VERSION 5.7 ;
BUSBITCHARS "[]" ;
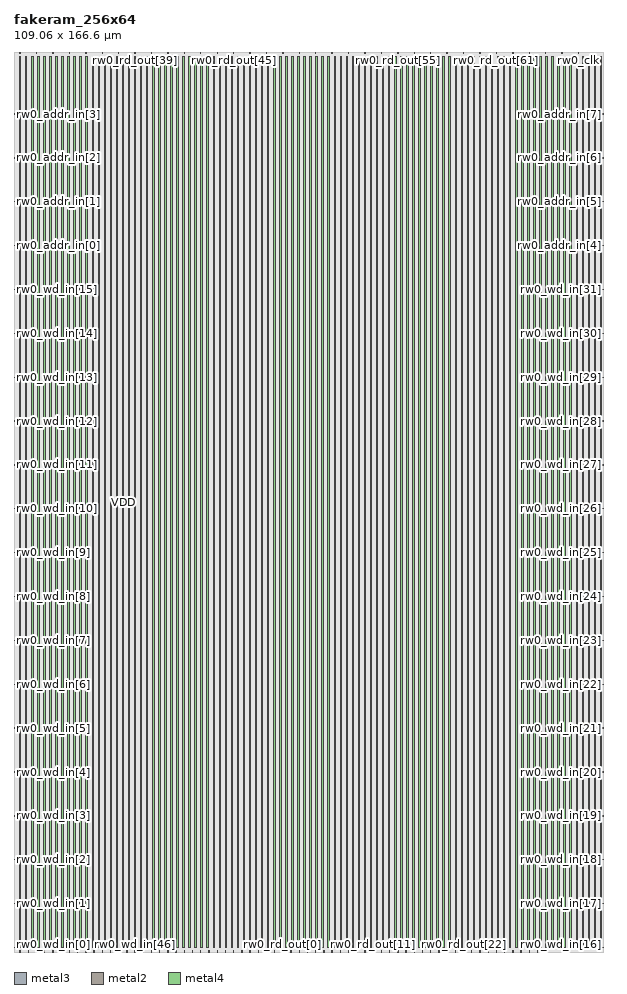
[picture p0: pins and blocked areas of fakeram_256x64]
MACRO fakeram_256x64
  FOREIGN fakeram_256x64 0 0 ;
  SYMMETRY X Y R90 ;
  SIZE 109.060 BY 166.600 ;
  CLASS BLOCK ;
  PIN rw0_wd_in[0]
    DIRECTION INPUT ;
    USE SIGNAL ;
    SHAPE ABUTMENT ;
    PORT
      LAYER metal3 ;
      RECT 0.000 0.805 0.210 0.875 ;
    END
  END rw0_wd_in[0]
  PIN rw0_wd_in[1]
    DIRECTION INPUT ;
    USE SIGNAL ;
    SHAPE ABUTMENT ;
    PORT
      LAYER metal3 ;
      RECT 0.000 8.925 0.210 8.995 ;
    END
  END rw0_wd_in[1]
  PIN rw0_wd_in[2]
    DIRECTION INPUT ;
    USE SIGNAL ;
    SHAPE ABUTMENT ;
    PORT
      LAYER metal3 ;
      RECT 0.000 17.045 0.210 17.115 ;
    END
  END rw0_wd_in[2]
  PIN rw0_wd_in[3]
    DIRECTION INPUT ;
    USE SIGNAL ;
    SHAPE ABUTMENT ;
    PORT
      LAYER metal3 ;
      RECT 0.000 25.165 0.210 25.235 ;
    END
  END rw0_wd_in[3]
  PIN rw0_wd_in[4]
    DIRECTION INPUT ;
    USE SIGNAL ;
    SHAPE ABUTMENT ;
    PORT
      LAYER metal3 ;
      RECT 0.000 33.285 0.210 33.355 ;
    END
  END rw0_wd_in[4]
  PIN rw0_wd_in[5]
    DIRECTION INPUT ;
    USE SIGNAL ;
    SHAPE ABUTMENT ;
    PORT
      LAYER metal3 ;
      RECT 0.000 41.405 0.210 41.475 ;
    END
  END rw0_wd_in[5]
  PIN rw0_wd_in[6]
    DIRECTION INPUT ;
    USE SIGNAL ;
    SHAPE ABUTMENT ;
    PORT
      LAYER metal3 ;
      RECT 0.000 49.525 0.210 49.595 ;
    END
  END rw0_wd_in[6]
  PIN rw0_wd_in[7]
    DIRECTION INPUT ;
    USE SIGNAL ;
    SHAPE ABUTMENT ;
    PORT
      LAYER metal3 ;
      RECT 0.000 57.645 0.210 57.715 ;
    END
  END rw0_wd_in[7]
  PIN rw0_wd_in[8]
    DIRECTION INPUT ;
    USE SIGNAL ;
    SHAPE ABUTMENT ;
    PORT
      LAYER metal3 ;
      RECT 0.000 65.765 0.210 65.835 ;
    END
  END rw0_wd_in[8]
  PIN rw0_wd_in[9]
    DIRECTION INPUT ;
    USE SIGNAL ;
    SHAPE ABUTMENT ;
    PORT
      LAYER metal3 ;
      RECT 0.000 73.885 0.210 73.955 ;
    END
  END rw0_wd_in[9]
  PIN rw0_wd_in[10]
    DIRECTION INPUT ;
    USE SIGNAL ;
    SHAPE ABUTMENT ;
    PORT
      LAYER metal3 ;
      RECT 0.000 82.005 0.210 82.075 ;
    END
  END rw0_wd_in[10]
  PIN rw0_wd_in[11]
    DIRECTION INPUT ;
    USE SIGNAL ;
    SHAPE ABUTMENT ;
    PORT
      LAYER metal3 ;
      RECT 0.000 90.125 0.210 90.195 ;
    END
  END rw0_wd_in[11]
  PIN rw0_wd_in[12]
    DIRECTION INPUT ;
    USE SIGNAL ;
    SHAPE ABUTMENT ;
    PORT
      LAYER metal3 ;
      RECT 0.000 98.245 0.210 98.315 ;
    END
  END rw0_wd_in[12]
  PIN rw0_wd_in[13]
    DIRECTION INPUT ;
    USE SIGNAL ;
    SHAPE ABUTMENT ;
    PORT
      LAYER metal3 ;
      RECT 0.000 106.365 0.210 106.435 ;
    END
  END rw0_wd_in[13]
  PIN rw0_wd_in[14]
    DIRECTION INPUT ;
    USE SIGNAL ;
    SHAPE ABUTMENT ;
    PORT
      LAYER metal3 ;
      RECT 0.000 114.485 0.210 114.555 ;
    END
  END rw0_wd_in[14]
  PIN rw0_wd_in[15]
    DIRECTION INPUT ;
    USE SIGNAL ;
    SHAPE ABUTMENT ;
    PORT
      LAYER metal3 ;
      RECT 0.000 122.605 0.210 122.675 ;
    END
  END rw0_wd_in[15]
  PIN rw0_wd_in[16]
    DIRECTION INPUT ;
    USE SIGNAL ;
    SHAPE ABUTMENT ;
    PORT
      LAYER metal3 ;
      RECT 108.850 0.805 109.060 0.875 ;
    END
  END rw0_wd_in[16]
  PIN rw0_wd_in[17]
    DIRECTION INPUT ;
    USE SIGNAL ;
    SHAPE ABUTMENT ;
    PORT
      LAYER metal3 ;
      RECT 108.850 8.925 109.060 8.995 ;
    END
  END rw0_wd_in[17]
  PIN rw0_wd_in[18]
    DIRECTION INPUT ;
    USE SIGNAL ;
    SHAPE ABUTMENT ;
    PORT
      LAYER metal3 ;
      RECT 108.850 17.045 109.060 17.115 ;
    END
  END rw0_wd_in[18]
  PIN rw0_wd_in[19]
    DIRECTION INPUT ;
    USE SIGNAL ;
    SHAPE ABUTMENT ;
    PORT
      LAYER metal3 ;
      RECT 108.850 25.165 109.060 25.235 ;
    END
  END rw0_wd_in[19]
  PIN rw0_wd_in[20]
    DIRECTION INPUT ;
    USE SIGNAL ;
    SHAPE ABUTMENT ;
    PORT
      LAYER metal3 ;
      RECT 108.850 33.285 109.060 33.355 ;
    END
  END rw0_wd_in[20]
  PIN rw0_wd_in[21]
    DIRECTION INPUT ;
    USE SIGNAL ;
    SHAPE ABUTMENT ;
    PORT
      LAYER metal3 ;
      RECT 108.850 41.405 109.060 41.475 ;
    END
  END rw0_wd_in[21]
  PIN rw0_wd_in[22]
    DIRECTION INPUT ;
    USE SIGNAL ;
    SHAPE ABUTMENT ;
    PORT
      LAYER metal3 ;
      RECT 108.850 49.525 109.060 49.595 ;
    END
  END rw0_wd_in[22]
  PIN rw0_wd_in[23]
    DIRECTION INPUT ;
    USE SIGNAL ;
    SHAPE ABUTMENT ;
    PORT
      LAYER metal3 ;
      RECT 108.850 57.645 109.060 57.715 ;
    END
  END rw0_wd_in[23]
  PIN rw0_wd_in[24]
    DIRECTION INPUT ;
    USE SIGNAL ;
    SHAPE ABUTMENT ;
    PORT
      LAYER metal3 ;
      RECT 108.850 65.765 109.060 65.835 ;
    END
  END rw0_wd_in[24]
  PIN rw0_wd_in[25]
    DIRECTION INPUT ;
    USE SIGNAL ;
    SHAPE ABUTMENT ;
    PORT
      LAYER metal3 ;
      RECT 108.850 73.885 109.060 73.955 ;
    END
  END rw0_wd_in[25]
  PIN rw0_wd_in[26]
    DIRECTION INPUT ;
    USE SIGNAL ;
    SHAPE ABUTMENT ;
    PORT
      LAYER metal3 ;
      RECT 108.850 82.005 109.060 82.075 ;
    END
  END rw0_wd_in[26]
  PIN rw0_wd_in[27]
    DIRECTION INPUT ;
    USE SIGNAL ;
    SHAPE ABUTMENT ;
    PORT
      LAYER metal3 ;
      RECT 108.850 90.125 109.060 90.195 ;
    END
  END rw0_wd_in[27]
  PIN rw0_wd_in[28]
    DIRECTION INPUT ;
    USE SIGNAL ;
    SHAPE ABUTMENT ;
    PORT
      LAYER metal3 ;
      RECT 108.850 98.245 109.060 98.315 ;
    END
  END rw0_wd_in[28]
  PIN rw0_wd_in[29]
    DIRECTION INPUT ;
    USE SIGNAL ;
    SHAPE ABUTMENT ;
    PORT
      LAYER metal3 ;
      RECT 108.850 106.365 109.060 106.435 ;
    END
  END rw0_wd_in[29]
  PIN rw0_wd_in[30]
    DIRECTION INPUT ;
    USE SIGNAL ;
    SHAPE ABUTMENT ;
    PORT
      LAYER metal3 ;
      RECT 108.850 114.485 109.060 114.555 ;
    END
  END rw0_wd_in[30]
  PIN rw0_wd_in[31]
    DIRECTION INPUT ;
    USE SIGNAL ;
    SHAPE ABUTMENT ;
    PORT
      LAYER metal3 ;
      RECT 108.850 122.605 109.060 122.675 ;
    END
  END rw0_wd_in[31]
  PIN rw0_wd_in[32]
    DIRECTION INPUT ;
    USE SIGNAL ;
    SHAPE ABUTMENT ;
    PORT
      LAYER metal2 ;
      RECT 1.105 0.000 1.175 0.210 ;
    END
  END rw0_wd_in[32]
  PIN rw0_wd_in[33]
    DIRECTION INPUT ;
    USE SIGNAL ;
    SHAPE ABUTMENT ;
    PORT
      LAYER metal2 ;
      RECT 2.625 0.000 2.695 0.210 ;
    END
  END rw0_wd_in[33]
  PIN rw0_wd_in[34]
    DIRECTION INPUT ;
    USE SIGNAL ;
    SHAPE ABUTMENT ;
    PORT
      LAYER metal2 ;
      RECT 4.145 0.000 4.215 0.210 ;
    END
  END rw0_wd_in[34]
  PIN rw0_wd_in[35]
    DIRECTION INPUT ;
    USE SIGNAL ;
    SHAPE ABUTMENT ;
    PORT
      LAYER metal2 ;
      RECT 5.665 0.000 5.735 0.210 ;
    END
  END rw0_wd_in[35]
  PIN rw0_wd_in[36]
    DIRECTION INPUT ;
    USE SIGNAL ;
    SHAPE ABUTMENT ;
    PORT
      LAYER metal2 ;
      RECT 7.185 0.000 7.255 0.210 ;
    END
  END rw0_wd_in[36]
  PIN rw0_wd_in[37]
    DIRECTION INPUT ;
    USE SIGNAL ;
    SHAPE ABUTMENT ;
    PORT
      LAYER metal2 ;
      RECT 8.705 0.000 8.775 0.210 ;
    END
  END rw0_wd_in[37]
  PIN rw0_wd_in[38]
    DIRECTION INPUT ;
    USE SIGNAL ;
    SHAPE ABUTMENT ;
    PORT
      LAYER metal2 ;
      RECT 10.225 0.000 10.295 0.210 ;
    END
  END rw0_wd_in[38]
  PIN rw0_wd_in[39]
    DIRECTION INPUT ;
    USE SIGNAL ;
    SHAPE ABUTMENT ;
    PORT
      LAYER metal2 ;
      RECT 11.745 0.000 11.815 0.210 ;
    END
  END rw0_wd_in[39]
  PIN rw0_wd_in[40]
    DIRECTION INPUT ;
    USE SIGNAL ;
    SHAPE ABUTMENT ;
    PORT
      LAYER metal2 ;
      RECT 13.265 0.000 13.335 0.210 ;
    END
  END rw0_wd_in[40]
  PIN rw0_wd_in[41]
    DIRECTION INPUT ;
    USE SIGNAL ;
    SHAPE ABUTMENT ;
    PORT
      LAYER metal2 ;
      RECT 14.785 0.000 14.855 0.210 ;
    END
  END rw0_wd_in[41]
  PIN rw0_wd_in[42]
    DIRECTION INPUT ;
    USE SIGNAL ;
    SHAPE ABUTMENT ;
    PORT
      LAYER metal2 ;
      RECT 16.305 0.000 16.375 0.210 ;
    END
  END rw0_wd_in[42]
  PIN rw0_wd_in[43]
    DIRECTION INPUT ;
    USE SIGNAL ;
    SHAPE ABUTMENT ;
    PORT
      LAYER metal2 ;
      RECT 17.825 0.000 17.895 0.210 ;
    END
  END rw0_wd_in[43]
  PIN rw0_wd_in[44]
    DIRECTION INPUT ;
    USE SIGNAL ;
    SHAPE ABUTMENT ;
    PORT
      LAYER metal2 ;
      RECT 19.345 0.000 19.415 0.210 ;
    END
  END rw0_wd_in[44]
  PIN rw0_wd_in[45]
    DIRECTION INPUT ;
    USE SIGNAL ;
    SHAPE ABUTMENT ;
    PORT
      LAYER metal2 ;
      RECT 20.865 0.000 20.935 0.210 ;
    END
  END rw0_wd_in[45]
  PIN rw0_wd_in[46]
    DIRECTION INPUT ;
    USE SIGNAL ;
    SHAPE ABUTMENT ;
    PORT
      LAYER metal2 ;
      RECT 22.385 0.000 22.455 0.210 ;
    END
  END rw0_wd_in[46]
  PIN rw0_wd_in[47]
    DIRECTION INPUT ;
    USE SIGNAL ;
    SHAPE ABUTMENT ;
    PORT
      LAYER metal2 ;
      RECT 23.905 0.000 23.975 0.210 ;
    END
  END rw0_wd_in[47]
  PIN rw0_wd_in[48]
    DIRECTION INPUT ;
    USE SIGNAL ;
    SHAPE ABUTMENT ;
    PORT
      LAYER metal2 ;
      RECT 25.425 0.000 25.495 0.210 ;
    END
  END rw0_wd_in[48]
  PIN rw0_wd_in[49]
    DIRECTION INPUT ;
    USE SIGNAL ;
    SHAPE ABUTMENT ;
    PORT
      LAYER metal2 ;
      RECT 26.945 0.000 27.015 0.210 ;
    END
  END rw0_wd_in[49]
  PIN rw0_wd_in[50]
    DIRECTION INPUT ;
    USE SIGNAL ;
    SHAPE ABUTMENT ;
    PORT
      LAYER metal2 ;
      RECT 28.465 0.000 28.535 0.210 ;
    END
  END rw0_wd_in[50]
  PIN rw0_wd_in[51]
    DIRECTION INPUT ;
    USE SIGNAL ;
    SHAPE ABUTMENT ;
    PORT
      LAYER metal2 ;
      RECT 29.985 0.000 30.055 0.210 ;
    END
  END rw0_wd_in[51]
  PIN rw0_wd_in[52]
    DIRECTION INPUT ;
    USE SIGNAL ;
    SHAPE ABUTMENT ;
    PORT
      LAYER metal2 ;
      RECT 31.505 0.000 31.575 0.210 ;
    END
  END rw0_wd_in[52]
  PIN rw0_wd_in[53]
    DIRECTION INPUT ;
    USE SIGNAL ;
    SHAPE ABUTMENT ;
    PORT
      LAYER metal2 ;
      RECT 33.025 0.000 33.095 0.210 ;
    END
  END rw0_wd_in[53]
  PIN rw0_wd_in[54]
    DIRECTION INPUT ;
    USE SIGNAL ;
    SHAPE ABUTMENT ;
    PORT
      LAYER metal2 ;
      RECT 34.545 0.000 34.615 0.210 ;
    END
  END rw0_wd_in[54]
  PIN rw0_wd_in[55]
    DIRECTION INPUT ;
    USE SIGNAL ;
    SHAPE ABUTMENT ;
    PORT
      LAYER metal2 ;
      RECT 36.065 0.000 36.135 0.210 ;
    END
  END rw0_wd_in[55]
  PIN rw0_wd_in[56]
    DIRECTION INPUT ;
    USE SIGNAL ;
    SHAPE ABUTMENT ;
    PORT
      LAYER metal2 ;
      RECT 37.585 0.000 37.655 0.210 ;
    END
  END rw0_wd_in[56]
  PIN rw0_wd_in[57]
    DIRECTION INPUT ;
    USE SIGNAL ;
    SHAPE ABUTMENT ;
    PORT
      LAYER metal2 ;
      RECT 39.105 0.000 39.175 0.210 ;
    END
  END rw0_wd_in[57]
  PIN rw0_wd_in[58]
    DIRECTION INPUT ;
    USE SIGNAL ;
    SHAPE ABUTMENT ;
    PORT
      LAYER metal2 ;
      RECT 40.625 0.000 40.695 0.210 ;
    END
  END rw0_wd_in[58]
  PIN rw0_wd_in[59]
    DIRECTION INPUT ;
    USE SIGNAL ;
    SHAPE ABUTMENT ;
    PORT
      LAYER metal2 ;
      RECT 42.145 0.000 42.215 0.210 ;
    END
  END rw0_wd_in[59]
  PIN rw0_wd_in[60]
    DIRECTION INPUT ;
    USE SIGNAL ;
    SHAPE ABUTMENT ;
    PORT
      LAYER metal2 ;
      RECT 43.665 0.000 43.735 0.210 ;
    END
  END rw0_wd_in[60]
  PIN rw0_wd_in[61]
    DIRECTION INPUT ;
    USE SIGNAL ;
    SHAPE ABUTMENT ;
    PORT
      LAYER metal2 ;
      RECT 45.185 0.000 45.255 0.210 ;
    END
  END rw0_wd_in[61]
  PIN rw0_wd_in[62]
    DIRECTION INPUT ;
    USE SIGNAL ;
    SHAPE ABUTMENT ;
    PORT
      LAYER metal2 ;
      RECT 46.705 0.000 46.775 0.210 ;
    END
  END rw0_wd_in[62]
  PIN rw0_wd_in[63]
    DIRECTION INPUT ;
    USE SIGNAL ;
    SHAPE ABUTMENT ;
    PORT
      LAYER metal2 ;
      RECT 48.225 0.000 48.295 0.210 ;
    END
  END rw0_wd_in[63]
  PIN rw0_rd_out[0]
    DIRECTION OUTPUT ;
    USE SIGNAL ;
    SHAPE ABUTMENT ;
    PORT
      LAYER metal2 ;
      RECT 49.745 0.000 49.815 0.210 ;
    END
  END rw0_rd_out[0]
  PIN rw0_rd_out[1]
    DIRECTION OUTPUT ;
    USE SIGNAL ;
    SHAPE ABUTMENT ;
    PORT
      LAYER metal2 ;
      RECT 51.265 0.000 51.335 0.210 ;
    END
  END rw0_rd_out[1]
  PIN rw0_rd_out[2]
    DIRECTION OUTPUT ;
    USE SIGNAL ;
    SHAPE ABUTMENT ;
    PORT
      LAYER metal2 ;
      RECT 52.785 0.000 52.855 0.210 ;
    END
  END rw0_rd_out[2]
  PIN rw0_rd_out[3]
    DIRECTION OUTPUT ;
    USE SIGNAL ;
    SHAPE ABUTMENT ;
    PORT
      LAYER metal2 ;
      RECT 54.305 0.000 54.375 0.210 ;
    END
  END rw0_rd_out[3]
  PIN rw0_rd_out[4]
    DIRECTION OUTPUT ;
    USE SIGNAL ;
    SHAPE ABUTMENT ;
    PORT
      LAYER metal2 ;
      RECT 55.825 0.000 55.895 0.210 ;
    END
  END rw0_rd_out[4]
  PIN rw0_rd_out[5]
    DIRECTION OUTPUT ;
    USE SIGNAL ;
    SHAPE ABUTMENT ;
    PORT
      LAYER metal2 ;
      RECT 57.345 0.000 57.415 0.210 ;
    END
  END rw0_rd_out[5]
  PIN rw0_rd_out[6]
    DIRECTION OUTPUT ;
    USE SIGNAL ;
    SHAPE ABUTMENT ;
    PORT
      LAYER metal2 ;
      RECT 58.865 0.000 58.935 0.210 ;
    END
  END rw0_rd_out[6]
  PIN rw0_rd_out[7]
    DIRECTION OUTPUT ;
    USE SIGNAL ;
    SHAPE ABUTMENT ;
    PORT
      LAYER metal2 ;
      RECT 60.385 0.000 60.455 0.210 ;
    END
  END rw0_rd_out[7]
  PIN rw0_rd_out[8]
    DIRECTION OUTPUT ;
    USE SIGNAL ;
    SHAPE ABUTMENT ;
    PORT
      LAYER metal2 ;
      RECT 61.905 0.000 61.975 0.210 ;
    END
  END rw0_rd_out[8]
  PIN rw0_rd_out[9]
    DIRECTION OUTPUT ;
    USE SIGNAL ;
    SHAPE ABUTMENT ;
    PORT
      LAYER metal2 ;
      RECT 63.425 0.000 63.495 0.210 ;
    END
  END rw0_rd_out[9]
  PIN rw0_rd_out[10]
    DIRECTION OUTPUT ;
    USE SIGNAL ;
    SHAPE ABUTMENT ;
    PORT
      LAYER metal2 ;
      RECT 64.945 0.000 65.015 0.210 ;
    END
  END rw0_rd_out[10]
  PIN rw0_rd_out[11]
    DIRECTION OUTPUT ;
    USE SIGNAL ;
    SHAPE ABUTMENT ;
    PORT
      LAYER metal2 ;
      RECT 66.465 0.000 66.535 0.210 ;
    END
  END rw0_rd_out[11]
  PIN rw0_rd_out[12]
    DIRECTION OUTPUT ;
    USE SIGNAL ;
    SHAPE ABUTMENT ;
    PORT
      LAYER metal2 ;
      RECT 67.985 0.000 68.055 0.210 ;
    END
  END rw0_rd_out[12]
  PIN rw0_rd_out[13]
    DIRECTION OUTPUT ;
    USE SIGNAL ;
    SHAPE ABUTMENT ;
    PORT
      LAYER metal2 ;
      RECT 69.505 0.000 69.575 0.210 ;
    END
  END rw0_rd_out[13]
  PIN rw0_rd_out[14]
    DIRECTION OUTPUT ;
    USE SIGNAL ;
    SHAPE ABUTMENT ;
    PORT
      LAYER metal2 ;
      RECT 71.025 0.000 71.095 0.210 ;
    END
  END rw0_rd_out[14]
  PIN rw0_rd_out[15]
    DIRECTION OUTPUT ;
    USE SIGNAL ;
    SHAPE ABUTMENT ;
    PORT
      LAYER metal2 ;
      RECT 72.545 0.000 72.615 0.210 ;
    END
  END rw0_rd_out[15]
  PIN rw0_rd_out[16]
    DIRECTION OUTPUT ;
    USE SIGNAL ;
    SHAPE ABUTMENT ;
    PORT
      LAYER metal2 ;
      RECT 74.065 0.000 74.135 0.210 ;
    END
  END rw0_rd_out[16]
  PIN rw0_rd_out[17]
    DIRECTION OUTPUT ;
    USE SIGNAL ;
    SHAPE ABUTMENT ;
    PORT
      LAYER metal2 ;
      RECT 75.585 0.000 75.655 0.210 ;
    END
  END rw0_rd_out[17]
  PIN rw0_rd_out[18]
    DIRECTION OUTPUT ;
    USE SIGNAL ;
    SHAPE ABUTMENT ;
    PORT
      LAYER metal2 ;
      RECT 77.105 0.000 77.175 0.210 ;
    END
  END rw0_rd_out[18]
  PIN rw0_rd_out[19]
    DIRECTION OUTPUT ;
    USE SIGNAL ;
    SHAPE ABUTMENT ;
    PORT
      LAYER metal2 ;
      RECT 78.625 0.000 78.695 0.210 ;
    END
  END rw0_rd_out[19]
  PIN rw0_rd_out[20]
    DIRECTION OUTPUT ;
    USE SIGNAL ;
    SHAPE ABUTMENT ;
    PORT
      LAYER metal2 ;
      RECT 80.145 0.000 80.215 0.210 ;
    END
  END rw0_rd_out[20]
  PIN rw0_rd_out[21]
    DIRECTION OUTPUT ;
    USE SIGNAL ;
    SHAPE ABUTMENT ;
    PORT
      LAYER metal2 ;
      RECT 81.665 0.000 81.735 0.210 ;
    END
  END rw0_rd_out[21]
  PIN rw0_rd_out[22]
    DIRECTION OUTPUT ;
    USE SIGNAL ;
    SHAPE ABUTMENT ;
    PORT
      LAYER metal2 ;
      RECT 83.185 0.000 83.255 0.210 ;
    END
  END rw0_rd_out[22]
  PIN rw0_rd_out[23]
    DIRECTION OUTPUT ;
    USE SIGNAL ;
    SHAPE ABUTMENT ;
    PORT
      LAYER metal2 ;
      RECT 84.705 0.000 84.775 0.210 ;
    END
  END rw0_rd_out[23]
  PIN rw0_rd_out[24]
    DIRECTION OUTPUT ;
    USE SIGNAL ;
    SHAPE ABUTMENT ;
    PORT
      LAYER metal2 ;
      RECT 86.225 0.000 86.295 0.210 ;
    END
  END rw0_rd_out[24]
  PIN rw0_rd_out[25]
    DIRECTION OUTPUT ;
    USE SIGNAL ;
    SHAPE ABUTMENT ;
    PORT
      LAYER metal2 ;
      RECT 87.745 0.000 87.815 0.210 ;
    END
  END rw0_rd_out[25]
  PIN rw0_rd_out[26]
    DIRECTION OUTPUT ;
    USE SIGNAL ;
    SHAPE ABUTMENT ;
    PORT
      LAYER metal2 ;
      RECT 89.265 0.000 89.335 0.210 ;
    END
  END rw0_rd_out[26]
  PIN rw0_rd_out[27]
    DIRECTION OUTPUT ;
    USE SIGNAL ;
    SHAPE ABUTMENT ;
    PORT
      LAYER metal2 ;
      RECT 90.785 0.000 90.855 0.210 ;
    END
  END rw0_rd_out[27]
  PIN rw0_rd_out[28]
    DIRECTION OUTPUT ;
    USE SIGNAL ;
    SHAPE ABUTMENT ;
    PORT
      LAYER metal2 ;
      RECT 92.305 0.000 92.375 0.210 ;
    END
  END rw0_rd_out[28]
  PIN rw0_rd_out[29]
    DIRECTION OUTPUT ;
    USE SIGNAL ;
    SHAPE ABUTMENT ;
    PORT
      LAYER metal2 ;
      RECT 93.825 0.000 93.895 0.210 ;
    END
  END rw0_rd_out[29]
  PIN rw0_rd_out[30]
    DIRECTION OUTPUT ;
    USE SIGNAL ;
    SHAPE ABUTMENT ;
    PORT
      LAYER metal2 ;
      RECT 95.345 0.000 95.415 0.210 ;
    END
  END rw0_rd_out[30]
  PIN rw0_rd_out[31]
    DIRECTION OUTPUT ;
    USE SIGNAL ;
    SHAPE ABUTMENT ;
    PORT
      LAYER metal2 ;
      RECT 96.865 0.000 96.935 0.210 ;
    END
  END rw0_rd_out[31]
  PIN rw0_rd_out[32]
    DIRECTION OUTPUT ;
    USE SIGNAL ;
    SHAPE ABUTMENT ;
    PORT
      LAYER metal2 ;
      RECT 1.105 166.390 1.175 166.600 ;
    END
  END rw0_rd_out[32]
  PIN rw0_rd_out[33]
    DIRECTION OUTPUT ;
    USE SIGNAL ;
    SHAPE ABUTMENT ;
    PORT
      LAYER metal2 ;
      RECT 4.145 166.390 4.215 166.600 ;
    END
  END rw0_rd_out[33]
  PIN rw0_rd_out[34]
    DIRECTION OUTPUT ;
    USE SIGNAL ;
    SHAPE ABUTMENT ;
    PORT
      LAYER metal2 ;
      RECT 7.185 166.390 7.255 166.600 ;
    END
  END rw0_rd_out[34]
  PIN rw0_rd_out[35]
    DIRECTION OUTPUT ;
    USE SIGNAL ;
    SHAPE ABUTMENT ;
    PORT
      LAYER metal2 ;
      RECT 10.225 166.390 10.295 166.600 ;
    END
  END rw0_rd_out[35]
  PIN rw0_rd_out[36]
    DIRECTION OUTPUT ;
    USE SIGNAL ;
    SHAPE ABUTMENT ;
    PORT
      LAYER metal2 ;
      RECT 13.265 166.390 13.335 166.600 ;
    END
  END rw0_rd_out[36]
  PIN rw0_rd_out[37]
    DIRECTION OUTPUT ;
    USE SIGNAL ;
    SHAPE ABUTMENT ;
    PORT
      LAYER metal2 ;
      RECT 16.305 166.390 16.375 166.600 ;
    END
  END rw0_rd_out[37]
  PIN rw0_rd_out[38]
    DIRECTION OUTPUT ;
    USE SIGNAL ;
    SHAPE ABUTMENT ;
    PORT
      LAYER metal2 ;
      RECT 19.345 166.390 19.415 166.600 ;
    END
  END rw0_rd_out[38]
  PIN rw0_rd_out[39]
    DIRECTION OUTPUT ;
    USE SIGNAL ;
    SHAPE ABUTMENT ;
    PORT
      LAYER metal2 ;
      RECT 22.385 166.390 22.455 166.600 ;
    END
  END rw0_rd_out[39]
  PIN rw0_rd_out[40]
    DIRECTION OUTPUT ;
    USE SIGNAL ;
    SHAPE ABUTMENT ;
    PORT
      LAYER metal2 ;
      RECT 25.425 166.390 25.495 166.600 ;
    END
  END rw0_rd_out[40]
  PIN rw0_rd_out[41]
    DIRECTION OUTPUT ;
    USE SIGNAL ;
    SHAPE ABUTMENT ;
    PORT
      LAYER metal2 ;
      RECT 28.465 166.390 28.535 166.600 ;
    END
  END rw0_rd_out[41]
  PIN rw0_rd_out[42]
    DIRECTION OUTPUT ;
    USE SIGNAL ;
    SHAPE ABUTMENT ;
    PORT
      LAYER metal2 ;
      RECT 31.505 166.390 31.575 166.600 ;
    END
  END rw0_rd_out[42]
  PIN rw0_rd_out[43]
    DIRECTION OUTPUT ;
    USE SIGNAL ;
    SHAPE ABUTMENT ;
    PORT
      LAYER metal2 ;
      RECT 34.545 166.390 34.615 166.600 ;
    END
  END rw0_rd_out[43]
  PIN rw0_rd_out[44]
    DIRECTION OUTPUT ;
    USE SIGNAL ;
    SHAPE ABUTMENT ;
    PORT
      LAYER metal2 ;
      RECT 37.585 166.390 37.655 166.600 ;
    END
  END rw0_rd_out[44]
  PIN rw0_rd_out[45]
    DIRECTION OUTPUT ;
    USE SIGNAL ;
    SHAPE ABUTMENT ;
    PORT
      LAYER metal2 ;
      RECT 40.625 166.390 40.695 166.600 ;
    END
  END rw0_rd_out[45]
  PIN rw0_rd_out[46]
    DIRECTION OUTPUT ;
    USE SIGNAL ;
    SHAPE ABUTMENT ;
    PORT
      LAYER metal2 ;
      RECT 43.665 166.390 43.735 166.600 ;
    END
  END rw0_rd_out[46]
  PIN rw0_rd_out[47]
    DIRECTION OUTPUT ;
    USE SIGNAL ;
    SHAPE ABUTMENT ;
    PORT
      LAYER metal2 ;
      RECT 46.705 166.390 46.775 166.600 ;
    END
  END rw0_rd_out[47]
  PIN rw0_rd_out[48]
    DIRECTION OUTPUT ;
    USE SIGNAL ;
    SHAPE ABUTMENT ;
    PORT
      LAYER metal2 ;
      RECT 49.745 166.390 49.815 166.600 ;
    END
  END rw0_rd_out[48]
  PIN rw0_rd_out[49]
    DIRECTION OUTPUT ;
    USE SIGNAL ;
    SHAPE ABUTMENT ;
    PORT
      LAYER metal2 ;
      RECT 52.785 166.390 52.855 166.600 ;
    END
  END rw0_rd_out[49]
  PIN rw0_rd_out[50]
    DIRECTION OUTPUT ;
    USE SIGNAL ;
    SHAPE ABUTMENT ;
    PORT
      LAYER metal2 ;
      RECT 55.825 166.390 55.895 166.600 ;
    END
  END rw0_rd_out[50]
  PIN rw0_rd_out[51]
    DIRECTION OUTPUT ;
    USE SIGNAL ;
    SHAPE ABUTMENT ;
    PORT
      LAYER metal2 ;
      RECT 58.865 166.390 58.935 166.600 ;
    END
  END rw0_rd_out[51]
  PIN rw0_rd_out[52]
    DIRECTION OUTPUT ;
    USE SIGNAL ;
    SHAPE ABUTMENT ;
    PORT
      LAYER metal2 ;
      RECT 61.905 166.390 61.975 166.600 ;
    END
  END rw0_rd_out[52]
  PIN rw0_rd_out[53]
    DIRECTION OUTPUT ;
    USE SIGNAL ;
    SHAPE ABUTMENT ;
    PORT
      LAYER metal2 ;
      RECT 64.945 166.390 65.015 166.600 ;
    END
  END rw0_rd_out[53]
  PIN rw0_rd_out[54]
    DIRECTION OUTPUT ;
    USE SIGNAL ;
    SHAPE ABUTMENT ;
    PORT
      LAYER metal2 ;
      RECT 67.985 166.390 68.055 166.600 ;
    END
  END rw0_rd_out[54]
  PIN rw0_rd_out[55]
    DIRECTION OUTPUT ;
    USE SIGNAL ;
    SHAPE ABUTMENT ;
    PORT
      LAYER metal2 ;
      RECT 71.025 166.390 71.095 166.600 ;
    END
  END rw0_rd_out[55]
  PIN rw0_rd_out[56]
    DIRECTION OUTPUT ;
    USE SIGNAL ;
    SHAPE ABUTMENT ;
    PORT
      LAYER metal2 ;
      RECT 74.065 166.390 74.135 166.600 ;
    END
  END rw0_rd_out[56]
  PIN rw0_rd_out[57]
    DIRECTION OUTPUT ;
    USE SIGNAL ;
    SHAPE ABUTMENT ;
    PORT
      LAYER metal2 ;
      RECT 77.105 166.390 77.175 166.600 ;
    END
  END rw0_rd_out[57]
  PIN rw0_rd_out[58]
    DIRECTION OUTPUT ;
    USE SIGNAL ;
    SHAPE ABUTMENT ;
    PORT
      LAYER metal2 ;
      RECT 80.145 166.390 80.215 166.600 ;
    END
  END rw0_rd_out[58]
  PIN rw0_rd_out[59]
    DIRECTION OUTPUT ;
    USE SIGNAL ;
    SHAPE ABUTMENT ;
    PORT
      LAYER metal2 ;
      RECT 83.185 166.390 83.255 166.600 ;
    END
  END rw0_rd_out[59]
  PIN rw0_rd_out[60]
    DIRECTION OUTPUT ;
    USE SIGNAL ;
    SHAPE ABUTMENT ;
    PORT
      LAYER metal2 ;
      RECT 86.225 166.390 86.295 166.600 ;
    END
  END rw0_rd_out[60]
  PIN rw0_rd_out[61]
    DIRECTION OUTPUT ;
    USE SIGNAL ;
    SHAPE ABUTMENT ;
    PORT
      LAYER metal2 ;
      RECT 89.265 166.390 89.335 166.600 ;
    END
  END rw0_rd_out[61]
  PIN rw0_rd_out[62]
    DIRECTION OUTPUT ;
    USE SIGNAL ;
    SHAPE ABUTMENT ;
    PORT
      LAYER metal2 ;
      RECT 92.305 166.390 92.375 166.600 ;
    END
  END rw0_rd_out[62]
  PIN rw0_rd_out[63]
    DIRECTION OUTPUT ;
    USE SIGNAL ;
    SHAPE ABUTMENT ;
    PORT
      LAYER metal2 ;
      RECT 95.345 166.390 95.415 166.600 ;
    END
  END rw0_rd_out[63]
  PIN rw0_addr_in[0]
    DIRECTION INPUT ;
    USE SIGNAL ;
    SHAPE ABUTMENT ;
    PORT
      LAYER metal3 ;
      RECT 0.000 130.725 0.210 130.795 ;
    END
  END rw0_addr_in[0]
  PIN rw0_addr_in[1]
    DIRECTION INPUT ;
    USE SIGNAL ;
    SHAPE ABUTMENT ;
    PORT
      LAYER metal3 ;
      RECT 0.000 138.845 0.210 138.915 ;
    END
  END rw0_addr_in[1]
  PIN rw0_addr_in[2]
    DIRECTION INPUT ;
    USE SIGNAL ;
    SHAPE ABUTMENT ;
    PORT
      LAYER metal3 ;
      RECT 0.000 146.965 0.210 147.035 ;
    END
  END rw0_addr_in[2]
  PIN rw0_addr_in[3]
    DIRECTION INPUT ;
    USE SIGNAL ;
    SHAPE ABUTMENT ;
    PORT
      LAYER metal3 ;
      RECT 0.000 155.085 0.210 155.155 ;
    END
  END rw0_addr_in[3]
  PIN rw0_addr_in[4]
    DIRECTION INPUT ;
    USE SIGNAL ;
    SHAPE ABUTMENT ;
    PORT
      LAYER metal3 ;
      RECT 108.850 130.725 109.060 130.795 ;
    END
  END rw0_addr_in[4]
  PIN rw0_addr_in[5]
    DIRECTION INPUT ;
    USE SIGNAL ;
    SHAPE ABUTMENT ;
    PORT
      LAYER metal3 ;
      RECT 108.850 138.845 109.060 138.915 ;
    END
  END rw0_addr_in[5]
  PIN rw0_addr_in[6]
    DIRECTION INPUT ;
    USE SIGNAL ;
    SHAPE ABUTMENT ;
    PORT
      LAYER metal3 ;
      RECT 108.850 146.965 109.060 147.035 ;
    END
  END rw0_addr_in[6]
  PIN rw0_addr_in[7]
    DIRECTION INPUT ;
    USE SIGNAL ;
    SHAPE ABUTMENT ;
    PORT
      LAYER metal3 ;
      RECT 108.850 155.085 109.060 155.155 ;
    END
  END rw0_addr_in[7]
  PIN rw0_we_in
    DIRECTION INPUT ;
    USE SIGNAL ;
    SHAPE ABUTMENT ;
    PORT
      LAYER metal2 ;
      RECT 98.385 166.390 98.455 166.600 ;
    END
  END rw0_we_in
  PIN rw0_ce_in
    DIRECTION INPUT ;
    USE SIGNAL ;
    SHAPE ABUTMENT ;
    PORT
      LAYER metal2 ;
      RECT 101.425 166.390 101.495 166.600 ;
    END
  END rw0_ce_in
  PIN rw0_clk
    DIRECTION INPUT ;
    USE SIGNAL ;
    SHAPE ABUTMENT ;
    PORT
      LAYER metal2 ;
      RECT 104.465 166.390 104.535 166.600 ;
    END
  END rw0_clk
  PIN VSS
    DIRECTION INOUT ;
    USE GROUND ;
    PORT
      LAYER metal4 ;
      RECT 1.000 0.840 1.280 165.760 ;
      RECT 3.240 0.840 3.520 165.760 ;
      RECT 5.480 0.840 5.760 165.760 ;
      RECT 7.720 0.840 8.000 165.760 ;
      RECT 9.960 0.840 10.240 165.760 ;
      RECT 12.200 0.840 12.480 165.760 ;
      RECT 14.440 0.840 14.720 165.760 ;
      RECT 16.680 0.840 16.960 165.760 ;
      RECT 18.920 0.840 19.200 165.760 ;
      RECT 21.160 0.840 21.440 165.760 ;
      RECT 23.400 0.840 23.680 165.760 ;
      RECT 25.640 0.840 25.920 165.760 ;
      RECT 27.880 0.840 28.160 165.760 ;
      RECT 30.120 0.840 30.400 165.760 ;
      RECT 32.360 0.840 32.640 165.760 ;
      RECT 34.600 0.840 34.880 165.760 ;
      RECT 36.840 0.840 37.120 165.760 ;
      RECT 39.080 0.840 39.360 165.760 ;
      RECT 41.320 0.840 41.600 165.760 ;
      RECT 43.560 0.840 43.840 165.760 ;
      RECT 45.800 0.840 46.080 165.760 ;
      RECT 48.040 0.840 48.320 165.760 ;
      RECT 50.280 0.840 50.560 165.760 ;
      RECT 52.520 0.840 52.800 165.760 ;
      RECT 54.760 0.840 55.040 165.760 ;
      RECT 57.000 0.840 57.280 165.760 ;
      RECT 59.240 0.840 59.520 165.760 ;
      RECT 61.480 0.840 61.760 165.760 ;
      RECT 63.720 0.840 64.000 165.760 ;
      RECT 65.960 0.840 66.240 165.760 ;
      RECT 68.200 0.840 68.480 165.760 ;
      RECT 70.440 0.840 70.720 165.760 ;
      RECT 72.680 0.840 72.960 165.760 ;
      RECT 74.920 0.840 75.200 165.760 ;
      RECT 77.160 0.840 77.440 165.760 ;
      RECT 79.400 0.840 79.680 165.760 ;
      RECT 81.640 0.840 81.920 165.760 ;
      RECT 83.880 0.840 84.160 165.760 ;
      RECT 86.120 0.840 86.400 165.760 ;
      RECT 88.360 0.840 88.640 165.760 ;
      RECT 90.600 0.840 90.880 165.760 ;
      RECT 92.840 0.840 93.120 165.760 ;
      RECT 95.080 0.840 95.360 165.760 ;
      RECT 97.320 0.840 97.600 165.760 ;
      RECT 99.560 0.840 99.840 165.760 ;
      RECT 101.800 0.840 102.080 165.760 ;
      RECT 104.040 0.840 104.320 165.760 ;
      RECT 106.280 0.840 106.560 165.760 ;
      RECT 108.520 0.840 108.800 165.760 ;
    END
  END VSS
  PIN VDD
    DIRECTION INOUT ;
    USE POWER ;
    PORT
      LAYER metal4 ;
      RECT 2.120 0.840 2.400 165.760 ;
      RECT 4.360 0.840 4.640 165.760 ;
      RECT 6.600 0.840 6.880 165.760 ;
      RECT 8.840 0.840 9.120 165.760 ;
      RECT 11.080 0.840 11.360 165.760 ;
      RECT 13.320 0.840 13.600 165.760 ;
      RECT 15.560 0.840 15.840 165.760 ;
      RECT 17.800 0.840 18.080 165.760 ;
      RECT 20.040 0.840 20.320 165.760 ;
      RECT 22.280 0.840 22.560 165.760 ;
      RECT 24.520 0.840 24.800 165.760 ;
      RECT 26.760 0.840 27.040 165.760 ;
      RECT 29.000 0.840 29.280 165.760 ;
      RECT 31.240 0.840 31.520 165.760 ;
      RECT 33.480 0.840 33.760 165.760 ;
      RECT 35.720 0.840 36.000 165.760 ;
      RECT 37.960 0.840 38.240 165.760 ;
      RECT 40.200 0.840 40.480 165.760 ;
      RECT 42.440 0.840 42.720 165.760 ;
      RECT 44.680 0.840 44.960 165.760 ;
      RECT 46.920 0.840 47.200 165.760 ;
      RECT 49.160 0.840 49.440 165.760 ;
      RECT 51.400 0.840 51.680 165.760 ;
      RECT 53.640 0.840 53.920 165.760 ;
      RECT 55.880 0.840 56.160 165.760 ;
      RECT 58.120 0.840 58.400 165.760 ;
      RECT 60.360 0.840 60.640 165.760 ;
      RECT 62.600 0.840 62.880 165.760 ;
      RECT 64.840 0.840 65.120 165.760 ;
      RECT 67.080 0.840 67.360 165.760 ;
      RECT 69.320 0.840 69.600 165.760 ;
      RECT 71.560 0.840 71.840 165.760 ;
      RECT 73.800 0.840 74.080 165.760 ;
      RECT 76.040 0.840 76.320 165.760 ;
      RECT 78.280 0.840 78.560 165.760 ;
      RECT 80.520 0.840 80.800 165.760 ;
      RECT 82.760 0.840 83.040 165.760 ;
      RECT 85.000 0.840 85.280 165.760 ;
      RECT 87.240 0.840 87.520 165.760 ;
      RECT 89.480 0.840 89.760 165.760 ;
      RECT 91.720 0.840 92.000 165.760 ;
      RECT 93.960 0.840 94.240 165.760 ;
      RECT 96.200 0.840 96.480 165.760 ;
      RECT 98.440 0.840 98.720 165.760 ;
      RECT 100.680 0.840 100.960 165.760 ;
      RECT 102.920 0.840 103.200 165.760 ;
      RECT 105.160 0.840 105.440 165.760 ;
      RECT 107.400 0.840 107.680 165.760 ;
    END
  END VDD
  OBS
    LAYER metal1 ;
    RECT 0 0 109.060 166.600 ;
    LAYER metal2 ;
    RECT 0 0 109.060 166.600 ;
    LAYER metal3 ;
    RECT 0 0 109.060 166.600 ;
    LAYER metal4 ;
    RECT 0 0 109.060 166.600 ;
    LAYER OVERLAP ;
    RECT 0 0 109.060 166.600 ;
  END
END fakeram_256x64

END LIBRARY
